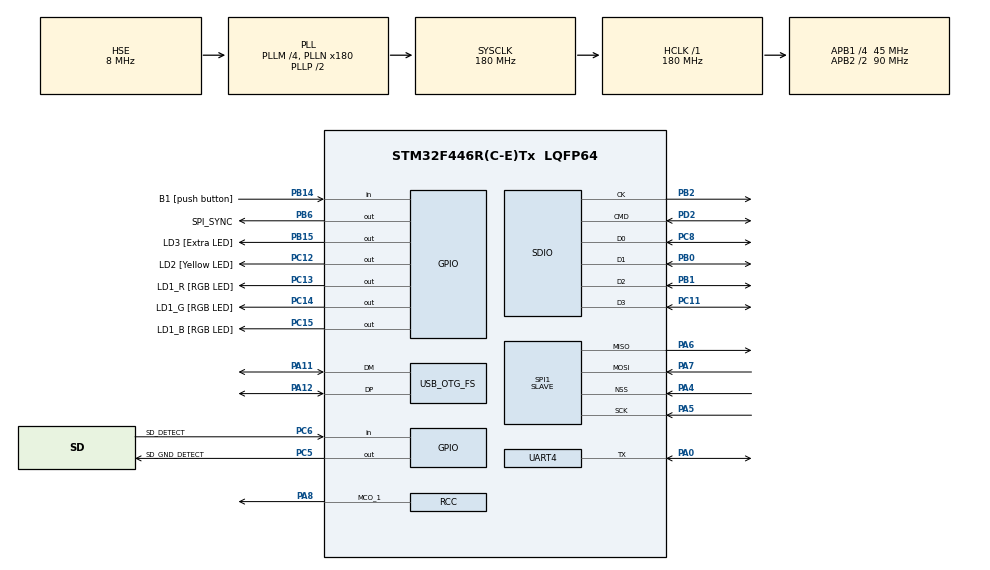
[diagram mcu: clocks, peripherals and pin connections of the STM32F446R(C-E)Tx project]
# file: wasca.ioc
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Dma.Request0=SPI1_RX
Dma.Request1=SPI1_TX
Dma.SPI1_RX.0.Direction=DMA_PERIPH_TO_MEMORY
Dma.SPI1_RX.0.FIFOMode=DMA_FIFOMODE_DISABLE
Dma.SPI1_RX.0.Instance=DMA2_Stream0
Dma.SPI1_RX.0.MemDataAlignment=DMA_MDATAALIGN_BYTE
Dma.SPI1_RX.0.MemInc=DMA_MINC_ENABLE
Dma.SPI1_RX.0.Mode=DMA_NORMAL
Dma.SPI1_RX.0.PeriphDataAlignment=DMA_PDATAALIGN_HALFWORD
Dma.SPI1_RX.0.PeriphInc=DMA_PINC_DISABLE
Dma.SPI1_RX.0.Priority=DMA_PRIORITY_VERY_HIGH
Dma.SPI1_TX.1.Direction=DMA_MEMORY_TO_PERIPH
Dma.SPI1_TX.1.FIFOMode=DMA_FIFOMODE_DISABLE
Dma.SPI1_TX.1.Instance=DMA2_Stream3
Dma.SPI1_TX.1.MemDataAlignment=DMA_MDATAALIGN_BYTE
Dma.SPI1_TX.1.MemInc=DMA_MINC_ENABLE
Dma.SPI1_TX.1.Mode=DMA_NORMAL
Dma.SPI1_TX.1.PeriphDataAlignment=DMA_PDATAALIGN_HALFWORD
Dma.SPI1_TX.1.PeriphInc=DMA_PINC_DISABLE
Dma.SPI1_TX.1.Priority=DMA_PRIORITY_VERY_HIGH
FATFS.BSP.number=1
FATFS0.BSP.STBoard=false
FATFS0.BSP.api=Unknown
FATFS0.BSP.i2caddr=0
FATFS0.BSP.instance=PC6
FATFS0.BSP.ip=GPIO
FATFS0.BSP.mode=Input
FATFS0.BSP.name=Detect_SDIO
FATFS0.BSP.solution=PC6
Mcu.Family=STM32F4
Mcu.Name=STM32F446R(C-E)Tx
Mcu.Package=LQFP64
NVIC.DMA2_Stream0_IRQn=true\:0\:0\:false\:false\:true\:false\:true
NVIC.DMA2_Stream3_IRQn=true\:0\:0\:false\:false\:true\:false\:true
NVIC.OTG_FS_IRQn=true\:0\:0\:false\:false\:true\:false\:true
NVIC.PriorityGroup=NVIC_PRIORITYGROUP_0
NVIC.SPI1_IRQn=true\:0\:0\:false\:false\:true\:true\:true
PA0-WKUP.Mode=Half_duplex(single_wire_mode)
PA0-WKUP.Signal=UART4_TX
PA11.Mode=Device_Only
PA11.Signal=USB_OTG_FS_DM
PA12.Mode=Device_Only
PA12.Signal=USB_OTG_FS_DP
PA13.GPIO_Label=TMS
PA13.Mode=JTAG_5_pins
PA13.Signal=SYS_JTMS-SWDIO
PA14.GPIO_Label=TCK
PA14.Mode=JTAG_5_pins
PA14.Signal=SYS_JTCK-SWCLK
PA15.Mode=JTAG_5_pins
PA15.Signal=SYS_JTDI
PA4.Mode=NSS_Signal_Hard_Input
PA4.Signal=SPI1_NSS
PA5.Mode=Full_Duplex_Slave
PA5.Signal=SPI1_SCK
PA6.Mode=Full_Duplex_Slave
PA6.Signal=SPI1_MISO
PA7.Mode=Full_Duplex_Slave
PA7.Signal=SPI1_MOSI
PA8.Mode=Clock-out-1
PA8.Signal=RCC_MCO_1
PB0.Mode=SD_4_bits_Wide_bus
PB0.Signal=SDIO_D1
PB1.Mode=SD_4_bits_Wide_bus
PB1.Signal=SDIO_D2
PB14.GPIO_Label=B1 [push button]
PB14.Signal=GPIO_Input
PB15.GPIO_Label=LD3 [Extra LED]
PB15.Signal=GPIO_Output
PB2.GPIO_PuPd=GPIO_NOPULL
PB2.Mode=SD_4_bits_Wide_bus
PB2.Signal=SDIO_CK
PB3.GPIO_Label=SWO
PB3.Mode=JTAG_5_pins
PB3.Signal=SYS_JTDO-SWO
PB4.Mode=JTAG_5_pins
PB4.Signal=SYS_JTRST
PB6.GPIO_Label=SPI_SYNC
PB6.GPIO_Speed=GPIO_SPEED_FREQ_VERY_HIGH
PB6.PinState=GPIO_PIN_SET
PB6.Signal=GPIO_Output
PC11.Mode=SD_4_bits_Wide_bus
PC11.Signal=SDIO_D3
PC12.GPIO_Label=LD2 [Yellow LED]
PC12.Signal=GPIO_Output
PC13.GPIO_Label=LD1_R [RGB LED]
PC13.Signal=GPIO_Output
PC14-OSC32_IN.GPIO_Label=LD1_G [RGB LED]
PC14-OSC32_IN.Signal=GPIO_Output
PC15-OSC32_OUT.GPIO_Label=LD1_B [RGB LED]
PC15-OSC32_OUT.Signal=GPIO_Output
PC5.GPIO_Label=SD_GND_DETECT
PC5.GPIO_PuPd=GPIO_PULLDOWN
PC5.Signal=GPIO_Output
PC6.GPIO_Label=SD_DETECT
PC6.Signal=GPIO_Input
PC8.Mode=SD_4_bits_Wide_bus
PC8.Signal=SDIO_D0
PD2.GPIO_PuPd=GPIO_NOPULL
PD2.Mode=SD_4_bits_Wide_bus
PD2.Signal=SDIO_CMD
PH0-OSC_IN.Mode=HSE-External-Oscillator
PH0-OSC_IN.Signal=RCC_OSC_IN
PH1-OSC_OUT.Mode=HSE-External-Oscillator
PH1-OSC_OUT.Signal=RCC_OSC_OUT
ProjectManager.HeapSize=0x4000
ProjectManager.StackSize=0x800
ProjectManager.TargetToolchain=Makefile
RCC.48MHZClocksFreq_Value=84000000
RCC.AHBFreq_Value=180000000
RCC.APB1CLKDivider=RCC_HCLK_DIV4
RCC.APB1Freq_Value=45000000
RCC.APB1TimFreq_Value=90000000
RCC.APB2CLKDivider=RCC_HCLK_DIV2
RCC.APB2Freq_Value=90000000
RCC.APB2TimFreq_Value=180000000
RCC.CortexFreq_Value=180000000
RCC.FLatency-AdvancedSettings=FLASH_LATENCY_5
RCC.HCLKFreq_Value=180000000
RCC.HSE_VALUE=8000000
RCC.HSI_VALUE=16000000
RCC.PLLM=4
RCC.PLLN=180
RCC.PLLQ=8
RCC.PLLSAIM=8
RCC.PLLSAIP=RCC_PLLSAIP_DIV4
RCC.RCC_MCO1Source=RCC_MCO1SOURCE_HSE
RCC.SYSCLKFreq_VALUE=180000000
RCC.SYSCLKSource=RCC_SYSCLKSOURCE_PLLCLK
RCC.USBCLockSelection=RCC_CLK48CLKSOURCE_PLLSAIP
RCC.USBFreq_Value=48000000
RCC.VCOOutputFreq_Value=360000000
SDIO.ClockDiv=0
SPI1.DataSize=SPI_DATASIZE_16BIT
SPI1.Direction=SPI_DIRECTION_2LINES
SPI1.Mode=SPI_MODE_SLAVE
SPI1.VirtualNSS=VM_NSSHARD
SPI1.VirtualType=VM_SLAVE
UART4.VirtualMode=Asynchronous
USB_DEVICE.CLASS_NAME_FS=CDC
USB_DEVICE.VirtualMode-CDC_FS=Cdc
USB_DEVICE.VirtualModeFS=Cdc_FS
USB_OTG_FS.VirtualMode=Device_Only
VP_CRC_VS_CRC.Mode=CRC_Activate
VP_FATFS_VS_SDIO.Mode=SDIO
VP_USB_DEVICE_VS_USB_DEVICE_CDC_FS.Mode=CDC_FS
board=NUCLEO-F446RE

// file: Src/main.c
/* USER CODE BEGIN Header */
/**
  ******************************************************************************
  * @file           : main.c
  * @brief          : Main program body
  ******************************************************************************
  * @attention
  *
  * <h2><center>&copy; Copyright (c) 2020 STMicroelectronics.
  * All rights reserved.</center></h2>
  *
  * This software component is licensed by ST under Ultimate Liberty license
  * SLA0044, the "License"; You may not use this file except in compliance with
  * the License. You may obtain a copy of the License at:
  *                             www.st.com/SLA0044
  *
  ******************************************************************************
  */
/* USER CODE END Header */
#include "main.h"
#include "fatfs.h"
#include "usb_device.h"

/* USER CODE BEGIN Includes */

#include <string.h>
#include "bup_bootrom.h"
#include "log.h"
#include "settings.h"
#include "spi_max10.h"
#include "spi_ping.h"
#include "misc_tests.h"
#include "sd_wrapper.h"

/* USER CODE END Includes */

SD_HandleTypeDef hsd;

SPI_HandleTypeDef hspi1;
DMA_HandleTypeDef hdma_spi1_rx;
DMA_HandleTypeDef hdma_spi1_tx;

UART_HandleTypeDef huart4;

/* USER CODE BEGIN PV */
/* Private variables ---------------------------------------------------------*/

/* USER CODE END PV */

void SystemClock_Config(void);
static void MX_GPIO_Init(void);
static void MX_DMA_Init(void);
static void MX_SDIO_SD_Init(void);
static void MX_SPI1_Init(void);
static void MX_UART4_Init(void);
/* USER CODE BEGIN PFP */
/* Private function prototypes -----------------------------------------------*/

/* USER CODE END PFP */

/* USER CODE BEGIN 0 */

// Redirect printf to UART
// Related information : http://www.openstm32.org/forumthread1346
int __io_putchar(int ch)
{
    HAL_UART_Transmit(&huart4, (uint8_t *)&ch, 1, 0xFFFF);

    return ch;
}
int _write(int file, char *ptr, int len)
{
    int DataIdx;

    for (DataIdx = 0; DataIdx < len; DataIdx++)
    {
        __io_putchar(*ptr++);
    }
    return len;
}

/* USER CODE END 0 */

int main(void)
{

  /* MCU Configuration--------------------------------------------------------*/

  /* Reset of all peripherals, Initializes the Flash interface and the Systick. */
  HAL_Init();

  /* USER CODE BEGIN Init */

  /* Reset base module's internals.
   * Note : SD card can't be accessed yet.
   */
  sdcard_reset();
  settings_init();
  log_init();

  /* USER CODE END Init */

  /* Configure the system clock */
  SystemClock_Config();

  /* Initialize all configured peripherals */
  MX_GPIO_Init();
  MX_DMA_Init();
  MX_SDIO_SD_Init();
  MX_FATFS_Init();
  MX_USB_DEVICE_Init();
  MX_SPI1_Init();
  MX_UART4_Init();
  /* USER CODE BEGIN 2 */

  /* Initialize SD card and FatFs.
   * After that it's the time to read settings from ini file in SD card.
   */
  sdcard_init();
  settings_read();

  /* Check if power is present on Saturn side */
  if (GPIO_PIN_SET == HAL_GPIO_ReadPin(SATURN_POWER_GPIO_Port, SATURN_POWER_Pin))
  {
    /* Power is present, enabling buffers */
    HAL_GPIO_WritePin(BUFFER_ENABLE_GPIO_Port, BUFFER_ENABLE_Pin, GPIO_PIN_RESET);
  }
  else
  {
    /* Power is not present, disabling buffers */
    HAL_GPIO_WritePin(BUFFER_ENABLE_GPIO_Port, BUFFER_ENABLE_Pin, GPIO_PIN_SET);
  }

  /* Initialize SPI internals. */
  spi_ping_init();
  spi_init();

  /* Update backup and boot ROM access modules. */
  bup_boot_init();

  /* Output a message to celebrate the end of initialization. */
  termout(WL_LOG_DEBUGNORMAL, "Wasca STM32 firmware build Date : %s, time : %s.", __DATE__, __TIME__);

  /* USER CODE END 2 */

  /* Infinite loop */
  /* USER CODE BEGIN WHILE */
  unsigned long logmsg_id = 0;

  /* Count the number of packets received between two time intervals. */
  unsigned long spi_init_cnt = 0;
  unsigned long prev_spi_init_cnt = spi_init_cnt;
  unsigned long prev_spi_init_tickcnt = HAL_GetTick();

  unsigned long prev_tick = HAL_GetTick();
  while (1)
  {
    /* Compute the number of packets exchanged in one second. */
    unsigned long spi_init_tickcnt = HAL_GetTick();
    unsigned long spi_tick_delta = spi_init_tickcnt - prev_spi_init_tickcnt;
    if(spi_tick_delta > 5)
    {
        unsigned long spi_packet_cnt = spi_init_cnt - prev_spi_init_cnt;
        unsigned long spi_packet_rate = (1000 * spi_packet_cnt) / spi_tick_delta;

        logout(WL_LOG_DEBUGNORMAL, "[%08X] ID[%2u] PKT/s[%4u] Tot[%5u]S[%5u]"
            , (unsigned int)HAL_GetTick()
            , (unsigned int)logmsg_id
            , (unsigned int)spi_packet_rate
            , (unsigned int)_spi_rcv_cnt
            , (unsigned int)_spi_shift_cnt);

        logmsg_id = (logmsg_id+1) % 100;
    }

    prev_spi_init_cnt = spi_init_cnt;
    prev_spi_init_tickcnt = spi_init_tickcnt;

    while(1)
    {
        // /* Send log message at a reasonable rate when blue button is released,
        //  * and like crazy when it is pushed.
        //  */
        //unsigned long log_period = (HAL_GPIO_ReadPin(B1_GPIO_Port, B1_Pin) == GPIO_PIN_RESET ? 10 : 500);
        unsigned long log_period = 1000;
        if((HAL_GetTick() - prev_tick) > log_period)
        {
            break;
        }

        /* If SPI communication is requested from MAX 10, process it here. */
        if(spi_periodic_check() == 1)
        {
            spi_init_cnt++;
        }

        /* Update backup data internals. */
        bup_periodic_check();

        /* If needed, write log messages from buffer to SD card. */
        log_periodic_check();

        /* Do miscellaneous tests. */
        do_tests();
    }

    prev_tick = HAL_GetTick();

    /* USER CODE END WHILE */

    /* USER CODE BEGIN 3 */

  }

  /* Terminate FatFs (never called). */
  termout(WL_LOG_DEBUGNORMAL, "FATFS_UnLinkDriver ...");
  FATFS_UnLinkDriver(SDPath);

  /* USER CODE END 3 */
}

void SystemClock_Config(void)
{
  RCC_OscInitTypeDef RCC_OscInitStruct = {0};
  RCC_ClkInitTypeDef RCC_ClkInitStruct = {0};
  RCC_PeriphCLKInitTypeDef PeriphClkInitStruct = {0};

  /** Configure the main internal regulator output voltage
  */
  __HAL_RCC_PWR_CLK_ENABLE();
  __HAL_PWR_VOLTAGESCALING_CONFIG(PWR_REGULATOR_VOLTAGE_SCALE1);
  /** Initializes the RCC Oscillators according to the specified parameters
  * in the RCC_OscInitTypeDef structure.
  */
  RCC_OscInitStruct.OscillatorType = RCC_OSCILLATORTYPE_HSE;
  RCC_OscInitStruct.HSEState = RCC_HSE_ON;
  RCC_OscInitStruct.PLL.PLLState = RCC_PLL_ON;
  RCC_OscInitStruct.PLL.PLLSource = RCC_PLLSOURCE_HSE;
  RCC_OscInitStruct.PLL.PLLM = 4;
  RCC_OscInitStruct.PLL.PLLN = 180;
  RCC_OscInitStruct.PLL.PLLP = RCC_PLLP_DIV2;
  RCC_OscInitStruct.PLL.PLLQ = 8;
  RCC_OscInitStruct.PLL.PLLR = 2;
  if (HAL_RCC_OscConfig(&RCC_OscInitStruct) != HAL_OK)
  {
    Error_Handler();
  }
  /** Activate the Over-Drive mode
  */
  if (HAL_PWREx_EnableOverDrive() != HAL_OK)
  {
    Error_Handler();
  }
  /** Initializes the CPU, AHB and APB buses clocks
  */
  RCC_ClkInitStruct.ClockType = RCC_CLOCKTYPE_HCLK|RCC_CLOCKTYPE_SYSCLK
                              |RCC_CLOCKTYPE_PCLK1|RCC_CLOCKTYPE_PCLK2;
  RCC_ClkInitStruct.SYSCLKSource = RCC_SYSCLKSOURCE_PLLCLK;
  RCC_ClkInitStruct.AHBCLKDivider = RCC_SYSCLK_DIV1;
  RCC_ClkInitStruct.APB1CLKDivider = RCC_HCLK_DIV4;
  RCC_ClkInitStruct.APB2CLKDivider = RCC_HCLK_DIV2;

  if (HAL_RCC_ClockConfig(&RCC_ClkInitStruct, FLASH_LATENCY_5) != HAL_OK)
  {
    Error_Handler();
  }
  PeriphClkInitStruct.PeriphClockSelection = RCC_PERIPHCLK_SDIO|RCC_PERIPHCLK_CLK48;
  PeriphClkInitStruct.PLLSAI.PLLSAIM = 8;
  PeriphClkInitStruct.PLLSAI.PLLSAIN = 192;
  PeriphClkInitStruct.PLLSAI.PLLSAIQ = 2;
  PeriphClkInitStruct.PLLSAI.PLLSAIP = RCC_PLLSAIP_DIV4;
  PeriphClkInitStruct.PLLSAIDivQ = 1;
  PeriphClkInitStruct.Clk48ClockSelection = RCC_CLK48CLKSOURCE_PLLSAIP;
  PeriphClkInitStruct.SdioClockSelection = RCC_SDIOCLKSOURCE_CLK48;
  if (HAL_RCCEx_PeriphCLKConfig(&PeriphClkInitStruct) != HAL_OK)
  {
    Error_Handler();
  }
  HAL_RCC_MCOConfig(RCC_MCO1, RCC_MCO1SOURCE_HSE, RCC_MCODIV_1);
}

static void MX_SDIO_SD_Init(void)
{

  hsd.Instance = SDIO;
  hsd.Init.ClockEdge = SDIO_CLOCK_EDGE_RISING;
  hsd.Init.ClockBypass = SDIO_CLOCK_BYPASS_DISABLE;
  hsd.Init.ClockPowerSave = SDIO_CLOCK_POWER_SAVE_DISABLE;
  hsd.Init.BusWide = SDIO_BUS_WIDE_1B;
  hsd.Init.HardwareFlowControl = SDIO_HARDWARE_FLOW_CONTROL_DISABLE;
  hsd.Init.ClockDiv = 0;

}

static void MX_SPI1_Init(void)
{

  /* SPI1 parameter configuration*/
  hspi1.Instance = SPI1;
  hspi1.Init.Mode = SPI_MODE_SLAVE;
  hspi1.Init.Direction = SPI_DIRECTION_2LINES;
  hspi1.Init.DataSize = SPI_DATASIZE_16BIT;
  hspi1.Init.CLKPolarity = SPI_POLARITY_LOW;
  hspi1.Init.CLKPhase = SPI_PHASE_1EDGE;
  hspi1.Init.NSS = SPI_NSS_SOFT;
  hspi1.Init.FirstBit = SPI_FIRSTBIT_MSB;
  hspi1.Init.TIMode = SPI_TIMODE_DISABLE;
  hspi1.Init.CRCCalculation = SPI_CRCCALCULATION_DISABLE;
  hspi1.Init.CRCPolynomial = 10;
  if (HAL_SPI_Init(&hspi1) != HAL_OK)
  {
    Error_Handler();
  }

}

static void MX_UART4_Init(void)
{

  huart4.Instance = UART4;
  huart4.Init.BaudRate = 115200;
  huart4.Init.WordLength = UART_WORDLENGTH_8B;
  huart4.Init.StopBits = UART_STOPBITS_1;
  huart4.Init.Parity = UART_PARITY_NONE;
  huart4.Init.Mode = UART_MODE_TX_RX;
  huart4.Init.HwFlowCtl = UART_HWCONTROL_NONE;
  huart4.Init.OverSampling = UART_OVERSAMPLING_16;
  if (HAL_HalfDuplex_Init(&huart4) != HAL_OK)
  {
    Error_Handler();
  }

}

static void MX_DMA_Init(void)
{

  /* DMA controller clock enable */
  __HAL_RCC_DMA2_CLK_ENABLE();

  /* DMA interrupt init */
  /* DMA2_Stream0_IRQn interrupt configuration */
  HAL_NVIC_SetPriority(DMA2_Stream0_IRQn, 0, 0);
  HAL_NVIC_EnableIRQ(DMA2_Stream0_IRQn);
  /* DMA2_Stream3_IRQn interrupt configuration */
  HAL_NVIC_SetPriority(DMA2_Stream3_IRQn, 0, 0);
  HAL_NVIC_EnableIRQ(DMA2_Stream3_IRQn);

}

static void MX_GPIO_Init(void)
{
  GPIO_InitTypeDef GPIO_InitStruct = {0};

  /* GPIO Ports Clock Enable */
  __HAL_RCC_GPIOC_CLK_ENABLE();
  __HAL_RCC_GPIOH_CLK_ENABLE();
  __HAL_RCC_GPIOA_CLK_ENABLE();
  __HAL_RCC_GPIOB_CLK_ENABLE();
  __HAL_RCC_GPIOD_CLK_ENABLE();

  /*Configure GPIO pin Output Level */
  HAL_GPIO_WritePin(GPIOC, LD1_R_Pin|LD1_G_Pin|LD1_B_Pin|SD_GND_DETECT_Pin
                          |LD2_Pin, GPIO_PIN_RESET);

  /*Configure GPIO pin Output Level */
  HAL_GPIO_WritePin(LD3_GPIO_Port, LD3_Pin, GPIO_PIN_RESET);

  /*Configure GPIO pin Output Level */
  HAL_GPIO_WritePin(SPI_SYNC_MISO_GPIO_Port, SPI_SYNC_MISO_Pin, GPIO_PIN_SET);

  /*Configure GPIO pin Output Level */
  HAL_GPIO_WritePin(BUFFER_ENABLE_GPIO_Port, BUFFER_ENABLE_Pin, GPIO_PIN_SET);//buffers are enabled at init

  /*Configure GPIO pins : LD1_R_Pin LD1_G_Pin LD1_B_Pin LD2_Pin */
  GPIO_InitStruct.Pin = LD1_R_Pin|LD1_G_Pin|LD1_B_Pin|LD2_Pin;
  GPIO_InitStruct.Mode = GPIO_MODE_OUTPUT_PP;
  GPIO_InitStruct.Pull = GPIO_NOPULL;
  GPIO_InitStruct.Speed = GPIO_SPEED_FREQ_LOW;
  HAL_GPIO_Init(GPIOC, &GPIO_InitStruct);

  /*Configure GPIO pin : SPI_SYNC_MOSI_Pin */
  GPIO_InitStruct.Pin = SPI_SYNC_MOSI_Pin;
  GPIO_InitStruct.Mode = GPIO_MODE_INPUT;
  GPIO_InitStruct.Pull = GPIO_NOPULL;
  HAL_GPIO_Init(SPI_SYNC_MOSI_GPIO_Port, &GPIO_InitStruct);

  /*Configure GPIO pin : SD_GND_DETECT_Pin */
  GPIO_InitStruct.Pin = SD_GND_DETECT_Pin;
  GPIO_InitStruct.Mode = GPIO_MODE_OUTPUT_PP;
  GPIO_InitStruct.Pull = GPIO_PULLDOWN;
  GPIO_InitStruct.Speed = GPIO_SPEED_FREQ_LOW;
  HAL_GPIO_Init(SD_GND_DETECT_GPIO_Port, &GPIO_InitStruct);

  /*Configure GPIO pin : B1_Pin */
  GPIO_InitStruct.Pin = B1_Pin;
  GPIO_InitStruct.Mode = GPIO_MODE_INPUT;
  GPIO_InitStruct.Pull = GPIO_NOPULL;
  HAL_GPIO_Init(B1_GPIO_Port, &GPIO_InitStruct);

  /*Configure GPIO pin : LD3_Pin */
  GPIO_InitStruct.Pin = LD3_Pin;
  GPIO_InitStruct.Mode = GPIO_MODE_OUTPUT_PP;
  GPIO_InitStruct.Pull = GPIO_NOPULL;
  GPIO_InitStruct.Speed = GPIO_SPEED_FREQ_LOW;
  HAL_GPIO_Init(LD3_GPIO_Port, &GPIO_InitStruct);

  /*Configure GPIO pin : SD_DETECT_Pin */
  GPIO_InitStruct.Pin = SD_DETECT_Pin;
  GPIO_InitStruct.Mode = GPIO_MODE_INPUT;
  GPIO_InitStruct.Pull = GPIO_NOPULL;
  HAL_GPIO_Init(SD_DETECT_GPIO_Port, &GPIO_InitStruct);

  /*Configure GPIO pin : PA8 */
  GPIO_InitStruct.Pin = GPIO_PIN_8;
  GPIO_InitStruct.Mode = GPIO_MODE_AF_PP;
  GPIO_InitStruct.Pull = GPIO_NOPULL;
  GPIO_InitStruct.Speed = GPIO_SPEED_FREQ_LOW;
  GPIO_InitStruct.Alternate = GPIO_AF0_MCO;
  HAL_GPIO_Init(GPIOA, &GPIO_InitStruct);

  /*Configure GPIO pin : SPI_SYNC_MISO_Pin */
  GPIO_InitStruct.Pin = SPI_SYNC_MISO_Pin;
  GPIO_InitStruct.Mode = GPIO_MODE_OUTPUT_PP;
  GPIO_InitStruct.Pull = GPIO_NOPULL;
  GPIO_InitStruct.Speed = GPIO_SPEED_FREQ_VERY_HIGH;
  HAL_GPIO_Init(SPI_SYNC_MISO_GPIO_Port, &GPIO_InitStruct);

  /*Configure GPIO pins : BUFFER_ENABLE */
  GPIO_InitStruct.Pin = BUFFER_ENABLE_Pin;
  GPIO_InitStruct.Mode = GPIO_MODE_OUTPUT_PP;
  GPIO_InitStruct.Pull = GPIO_NOPULL;
  GPIO_InitStruct.Speed = GPIO_SPEED_FREQ_LOW;
  HAL_GPIO_Init(BUFFER_ENABLE_GPIO_Port, &GPIO_InitStruct);

  /*Configure GPIO pins : SATURN_POWER */
  GPIO_InitStruct.Pin = SATURN_POWER_Pin;
  GPIO_InitStruct.Mode = GPIO_MODE_INPUT;
  GPIO_InitStruct.Pull = GPIO_PULLDOWN;
  HAL_GPIO_Init(SATURN_POWER_GPIO_Port, &GPIO_InitStruct);

}

void Error_Handler_Ex(const char* file, int line, const char* func)
{
  /* USER CODE BEGIN Error_Handler_Debug */
  /* User can add his own implementation to report the HAL error return state */

    logout(WL_LOG_ERROR,
        "Tick[0x%08X] Error_Handler at [%s::%d] [%s]"
        , (unsigned int)HAL_GetTick()
        , file
        , line
        , func
    );

    /* Make LD2 (green LED) blinking for a small while when error happens. */
    int i;
    for(i=0; i<3; i++)
    {
        HAL_GPIO_WritePin(GPIOA, LD2_Pin, GPIO_PIN_SET);
        HAL_Delay(200);
        HAL_GPIO_WritePin(GPIOA, LD2_Pin, GPIO_PIN_RESET);
        HAL_Delay(200);
    }

  //while(1)
  //{
  //}
  /* USER CODE END Error_Handler_Debug */
}

/************************ (C) COPYRIGHT STMicroelectronics *****END OF FILE****/
